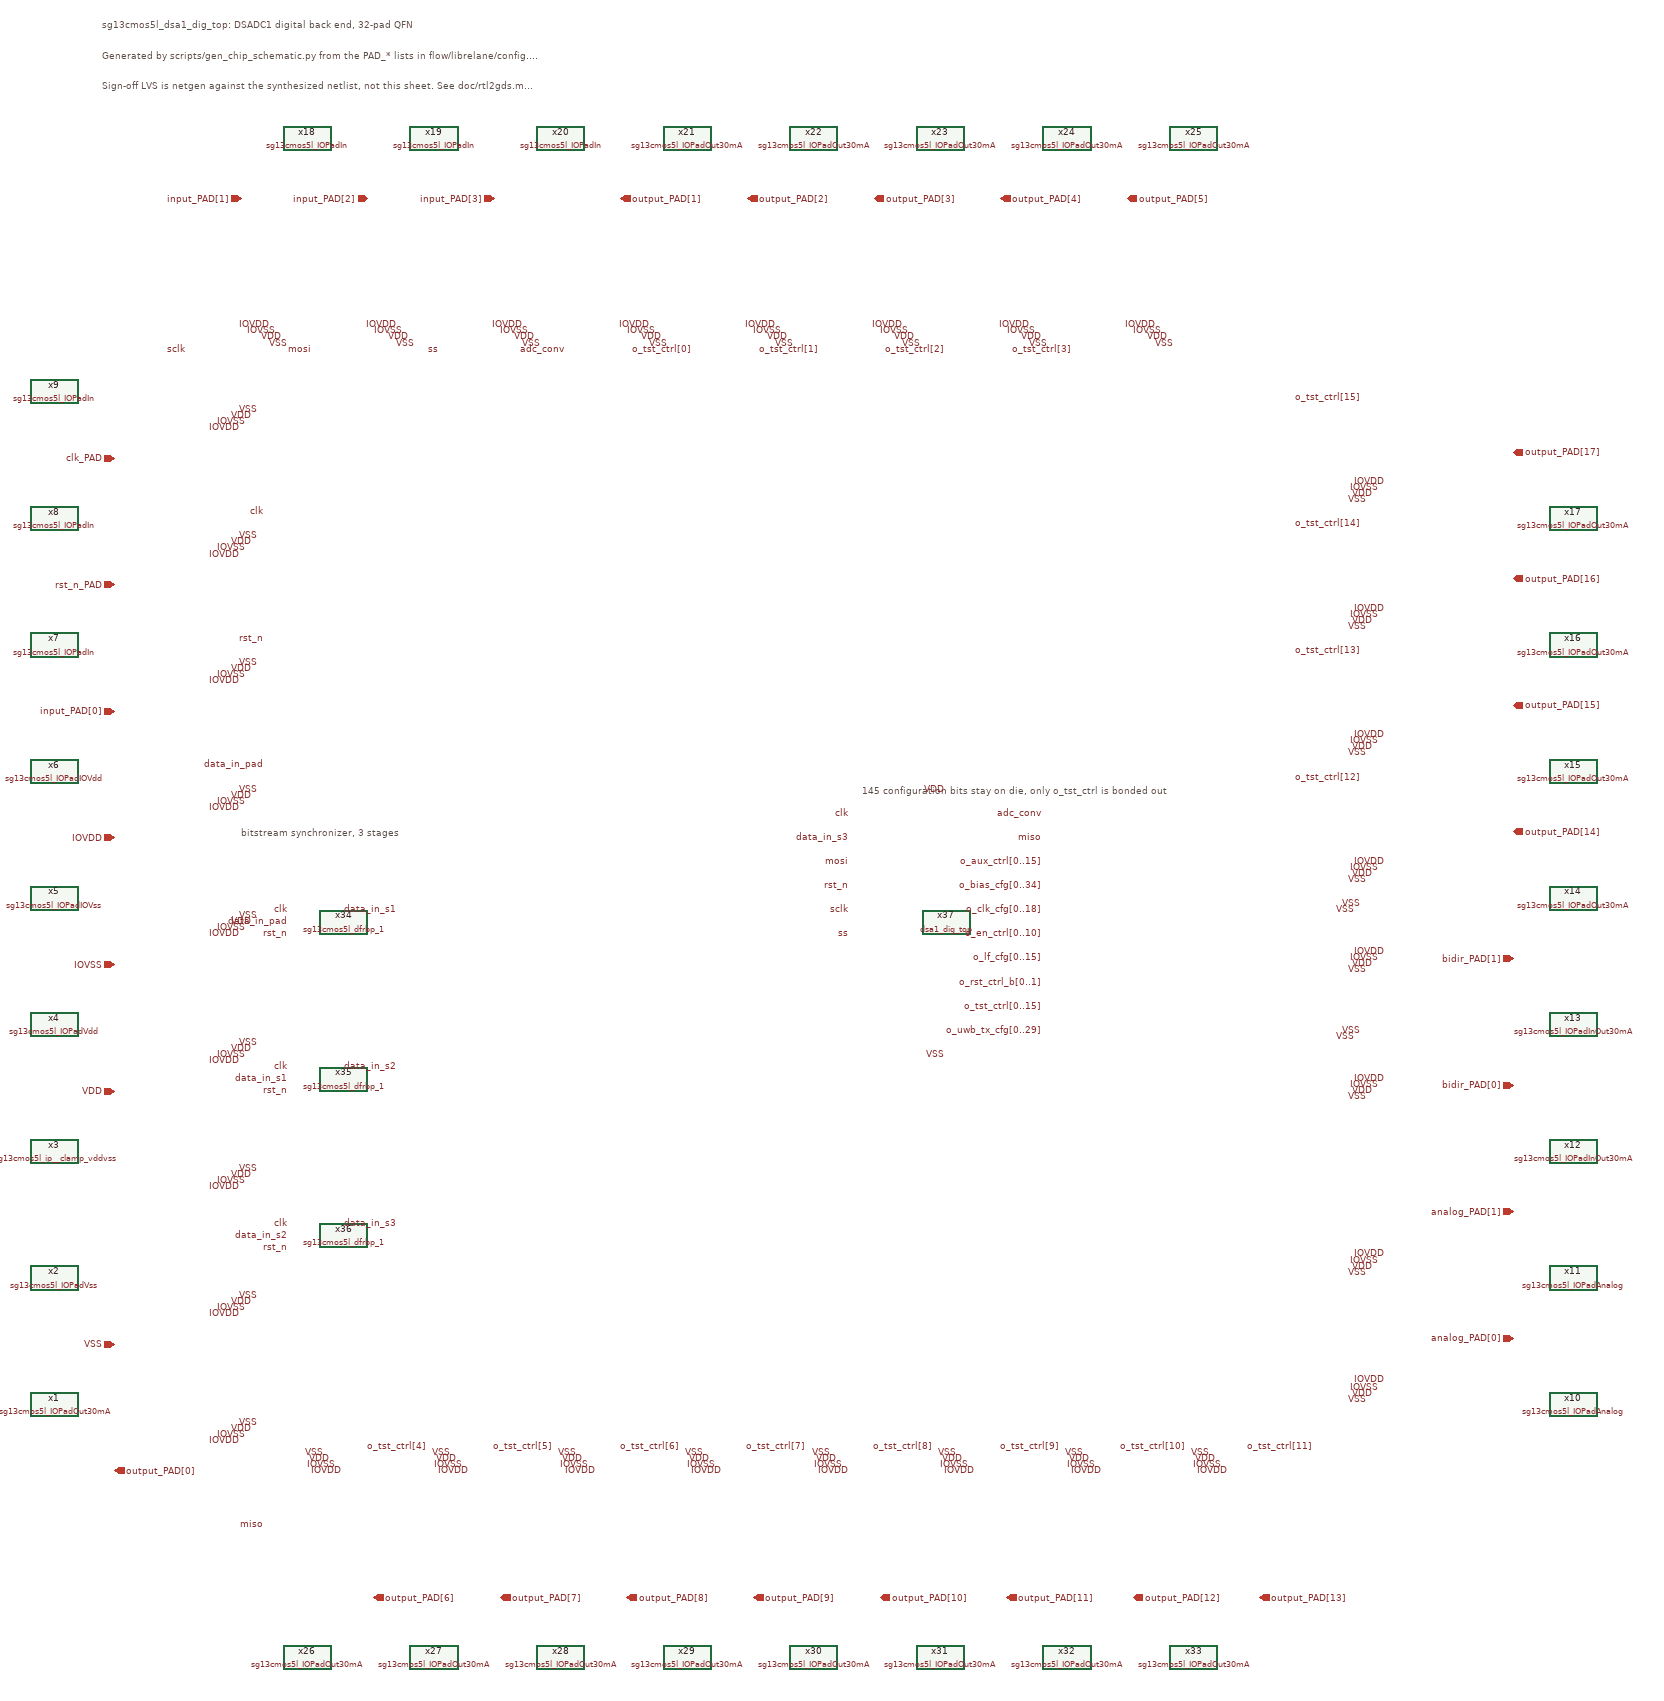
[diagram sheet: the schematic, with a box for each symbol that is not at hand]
v {xschem version=3.4.8RC file_version=1.3}
G {}
K {}
V {}
S {}
F {}
E {}
T {sg13cmos5l_dsa1_dig_top: DSADC1 digital back end, 32-pad QFN} 300 -3200 0 0 0.4 0.4 {}
T {Generated by scripts/gen_chip_schematic.py from the PAD_* lists in flow/librelane/config.yaml. Do not hand edit.} 300 -3150 0 0 0.4 0.4 {}
T {Sign-off LVS is netgen against the synthesized netlist, not this sheet. See doc/rtl2gds.md.} 300 -3100 0 0 0.4 0.4 {}
C {sg13cmos5l_io/sg13cmos5l_IOPadOut30mA.sym} 220 -900 1 0 {name=x1}
C {lab_pin.sym} 560 -870 0 0 {name=l1 sig_type=std_logic lab=VSS}
C {lab_pin.sym} 550 -860 0 0 {name=l2 sig_type=std_logic lab=VDD}
C {lab_pin.sym} 540 -850 0 0 {name=l3 sig_type=std_logic lab=IOVSS}
C {lab_pin.sym} 530 -840 0 0 {name=l4 sig_type=std_logic lab=IOVDD}
C {devices/opin.sym} 320 -790 1 0 {name=p1 lab=output_PAD[0]}
C {lab_pin.sym} 570 -700 0 0 {name=l5 sig_type=std_logic lab=miso}
C {sg13cmos5l_io/sg13cmos5l_IOPadVss.sym} 220 -1110 1 0 {name=x2}
C {lab_pin.sym} 560 -1080 0 0 {name=l6 sig_type=std_logic lab=VSS}
C {lab_pin.sym} 550 -1070 0 0 {name=l7 sig_type=std_logic lab=VDD}
C {lab_pin.sym} 540 -1060 0 0 {name=l8 sig_type=std_logic lab=IOVSS}
C {lab_pin.sym} 530 -1050 0 0 {name=l9 sig_type=std_logic lab=IOVDD}
C {devices/iopin.sym} 320 -1000 1 0 {name=p2 lab=VSS}
C {sg13cmos5l_ip__clamp_vddvss.sym} 220 -1320 1 0 {name=x3}
C {lab_pin.sym} 560 -1290 0 0 {name=l10 sig_type=std_logic lab=VSS}
C {lab_pin.sym} 550 -1280 0 0 {name=l11 sig_type=std_logic lab=VDD}
C {lab_pin.sym} 540 -1270 0 0 {name=l12 sig_type=std_logic lab=IOVSS}
C {lab_pin.sym} 530 -1260 0 0 {name=l13 sig_type=std_logic lab=IOVDD}
C {sg13cmos5l_io/sg13cmos5l_IOPadVdd.sym} 220 -1530 1 0 {name=x4}
C {lab_pin.sym} 560 -1500 0 0 {name=l14 sig_type=std_logic lab=VSS}
C {lab_pin.sym} 550 -1490 0 0 {name=l15 sig_type=std_logic lab=VDD}
C {lab_pin.sym} 540 -1480 0 0 {name=l16 sig_type=std_logic lab=IOVSS}
C {lab_pin.sym} 530 -1470 0 0 {name=l17 sig_type=std_logic lab=IOVDD}
C {devices/iopin.sym} 320 -1420 1 0 {name=p3 lab=VDD}
C {sg13cmos5l_io/sg13cmos5l_IOPadIOVss.sym} 220 -1740 1 0 {name=x5}
C {lab_pin.sym} 560 -1710 0 0 {name=l18 sig_type=std_logic lab=VSS}
C {lab_pin.sym} 550 -1700 0 0 {name=l19 sig_type=std_logic lab=VDD}
C {lab_pin.sym} 540 -1690 0 0 {name=l20 sig_type=std_logic lab=IOVSS}
C {lab_pin.sym} 530 -1680 0 0 {name=l21 sig_type=std_logic lab=IOVDD}
C {devices/iopin.sym} 320 -1630 1 0 {name=p4 lab=IOVSS}
C {sg13cmos5l_io/sg13cmos5l_IOPadIOVdd.sym} 220 -1950 1 0 {name=x6}
C {lab_pin.sym} 560 -1920 0 0 {name=l22 sig_type=std_logic lab=VSS}
C {lab_pin.sym} 550 -1910 0 0 {name=l23 sig_type=std_logic lab=VDD}
C {lab_pin.sym} 540 -1900 0 0 {name=l24 sig_type=std_logic lab=IOVSS}
C {lab_pin.sym} 530 -1890 0 0 {name=l25 sig_type=std_logic lab=IOVDD}
C {devices/iopin.sym} 320 -1840 1 0 {name=p5 lab=IOVDD}
C {sg13cmos5l_io/sg13cmos5l_IOPadIn.sym} 220 -2160 1 0 {name=x7}
C {lab_pin.sym} 560 -2130 0 0 {name=l26 sig_type=std_logic lab=VSS}
C {lab_pin.sym} 550 -2120 0 0 {name=l27 sig_type=std_logic lab=VDD}
C {lab_pin.sym} 540 -2110 0 0 {name=l28 sig_type=std_logic lab=IOVSS}
C {lab_pin.sym} 530 -2100 0 0 {name=l29 sig_type=std_logic lab=IOVDD}
C {devices/ipin.sym} 320 -2050 1 0 {name=p6 lab=input_PAD[0]}
C {lab_pin.sym} 570 -1960 0 0 {name=l30 sig_type=std_logic lab=data_in_pad}
C {sg13cmos5l_io/sg13cmos5l_IOPadIn.sym} 220 -2370 1 0 {name=x8}
C {lab_pin.sym} 560 -2340 0 0 {name=l31 sig_type=std_logic lab=VSS}
C {lab_pin.sym} 550 -2330 0 0 {name=l32 sig_type=std_logic lab=VDD}
C {lab_pin.sym} 540 -2320 0 0 {name=l33 sig_type=std_logic lab=IOVSS}
C {lab_pin.sym} 530 -2310 0 0 {name=l34 sig_type=std_logic lab=IOVDD}
C {devices/ipin.sym} 320 -2260 1 0 {name=p7 lab=rst_n_PAD}
C {lab_pin.sym} 570 -2170 0 0 {name=l35 sig_type=std_logic lab=rst_n}
C {sg13cmos5l_io/sg13cmos5l_IOPadIn.sym} 220 -2580 1 0 {name=x9}
C {lab_pin.sym} 560 -2550 0 0 {name=l36 sig_type=std_logic lab=VSS}
C {lab_pin.sym} 550 -2540 0 0 {name=l37 sig_type=std_logic lab=VDD}
C {lab_pin.sym} 540 -2530 0 0 {name=l38 sig_type=std_logic lab=IOVSS}
C {lab_pin.sym} 530 -2520 0 0 {name=l39 sig_type=std_logic lab=IOVDD}
C {devices/ipin.sym} 320 -2470 1 0 {name=p8 lab=clk_PAD}
C {lab_pin.sym} 570 -2380 0 0 {name=l40 sig_type=std_logic lab=clk}
C {sg13cmos5l_io/sg13cmos5l_IOPadAnalog.sym} 2740 -900 3 0 {name=x10}
C {lab_pin.sym} 2400 -908 0 0 {name=l41 sig_type=std_logic lab=VSS}
C {lab_pin.sym} 2410 -918 0 0 {name=l42 sig_type=std_logic lab=VDD}
C {lab_pin.sym} 2420 -928 0 0 {name=l43 sig_type=std_logic lab=IOVSS}
C {lab_pin.sym} 2430 -940 0 0 {name=l44 sig_type=std_logic lab=IOVDD}
C {devices/iopin.sym} 2640 -1010 3 0 {name=p9 lab=analog_PAD[0]}
C {noconn.sym} 2390 -1000 0 0 {name=nc_an0_pad}
C {noconn.sym} 2390 -1100 0 0 {name=nc_an0_padres}
C {sg13cmos5l_io/sg13cmos5l_IOPadAnalog.sym} 2740 -1110 3 0 {name=x11}
C {lab_pin.sym} 2400 -1118 0 0 {name=l45 sig_type=std_logic lab=VSS}
C {lab_pin.sym} 2410 -1128 0 0 {name=l46 sig_type=std_logic lab=VDD}
C {lab_pin.sym} 2420 -1138 0 0 {name=l47 sig_type=std_logic lab=IOVSS}
C {lab_pin.sym} 2430 -1150 0 0 {name=l48 sig_type=std_logic lab=IOVDD}
C {devices/iopin.sym} 2640 -1220 3 0 {name=p10 lab=analog_PAD[1]}
C {noconn.sym} 2390 -1210 0 0 {name=nc_an1_pad}
C {noconn.sym} 2390 -1310 0 0 {name=nc_an1_padres}
C {sg13cmos5l_io/sg13cmos5l_IOPadInOut30mA.sym} 2740 -1320 3 0 {name=x12}
C {lab_pin.sym} 2400 -1410 0 0 {name=l49 sig_type=std_logic lab=VSS}
C {lab_pin.sym} 2410 -1420 0 0 {name=l50 sig_type=std_logic lab=VDD}
C {lab_pin.sym} 2420 -1430 0 0 {name=l51 sig_type=std_logic lab=IOVSS}
C {lab_pin.sym} 2430 -1440 0 0 {name=l52 sig_type=std_logic lab=IOVDD}
C {devices/iopin.sym} 2640 -1430 3 0 {name=p11 lab=bidir_PAD[0]}
C {lab_pin.sym} 2390 -1520 0 0 {name=l53 sig_type=std_logic lab=VSS}
C {lab_pin.sym} 2380 -1510 0 0 {name=l54 sig_type=std_logic lab=VSS}
C {noconn.sym} 2380 -1330 0 0 {name=nc_bd0_p2c}
C {sg13cmos5l_io/sg13cmos5l_IOPadInOut30mA.sym} 2740 -1530 3 0 {name=x13}
C {lab_pin.sym} 2400 -1620 0 0 {name=l55 sig_type=std_logic lab=VSS}
C {lab_pin.sym} 2410 -1630 0 0 {name=l56 sig_type=std_logic lab=VDD}
C {lab_pin.sym} 2420 -1640 0 0 {name=l57 sig_type=std_logic lab=IOVSS}
C {lab_pin.sym} 2430 -1650 0 0 {name=l58 sig_type=std_logic lab=IOVDD}
C {devices/iopin.sym} 2640 -1640 3 0 {name=p12 lab=bidir_PAD[1]}
C {lab_pin.sym} 2390 -1730 0 0 {name=l59 sig_type=std_logic lab=VSS}
C {lab_pin.sym} 2380 -1720 0 0 {name=l60 sig_type=std_logic lab=VSS}
C {noconn.sym} 2380 -1540 0 0 {name=nc_bd1_p2c}
C {sg13cmos5l_io/sg13cmos5l_IOPadOut30mA.sym} 2740 -1740 3 0 {name=x14}
C {lab_pin.sym} 2400 -1770 0 0 {name=l61 sig_type=std_logic lab=VSS}
C {lab_pin.sym} 2410 -1780 0 0 {name=l62 sig_type=std_logic lab=VDD}
C {lab_pin.sym} 2420 -1790 0 0 {name=l63 sig_type=std_logic lab=IOVSS}
C {lab_pin.sym} 2430 -1800 0 0 {name=l64 sig_type=std_logic lab=IOVDD}
C {devices/opin.sym} 2640 -1850 3 0 {name=p13 lab=output_PAD[14]}
C {lab_pin.sym} 2390 -1940 0 0 {name=l65 sig_type=std_logic lab=o_tst_ctrl[12]}
C {sg13cmos5l_io/sg13cmos5l_IOPadOut30mA.sym} 2740 -1950 3 0 {name=x15}
C {lab_pin.sym} 2400 -1980 0 0 {name=l66 sig_type=std_logic lab=VSS}
C {lab_pin.sym} 2410 -1990 0 0 {name=l67 sig_type=std_logic lab=VDD}
C {lab_pin.sym} 2420 -2000 0 0 {name=l68 sig_type=std_logic lab=IOVSS}
C {lab_pin.sym} 2430 -2010 0 0 {name=l69 sig_type=std_logic lab=IOVDD}
C {devices/opin.sym} 2640 -2060 3 0 {name=p14 lab=output_PAD[15]}
C {lab_pin.sym} 2390 -2150 0 0 {name=l70 sig_type=std_logic lab=o_tst_ctrl[13]}
C {sg13cmos5l_io/sg13cmos5l_IOPadOut30mA.sym} 2740 -2160 3 0 {name=x16}
C {lab_pin.sym} 2400 -2190 0 0 {name=l71 sig_type=std_logic lab=VSS}
C {lab_pin.sym} 2410 -2200 0 0 {name=l72 sig_type=std_logic lab=VDD}
C {lab_pin.sym} 2420 -2210 0 0 {name=l73 sig_type=std_logic lab=IOVSS}
C {lab_pin.sym} 2430 -2220 0 0 {name=l74 sig_type=std_logic lab=IOVDD}
C {devices/opin.sym} 2640 -2270 3 0 {name=p15 lab=output_PAD[16]}
C {lab_pin.sym} 2390 -2360 0 0 {name=l75 sig_type=std_logic lab=o_tst_ctrl[14]}
C {sg13cmos5l_io/sg13cmos5l_IOPadOut30mA.sym} 2740 -2370 3 0 {name=x17}
C {lab_pin.sym} 2400 -2400 0 0 {name=l76 sig_type=std_logic lab=VSS}
C {lab_pin.sym} 2410 -2410 0 0 {name=l77 sig_type=std_logic lab=VDD}
C {lab_pin.sym} 2420 -2420 0 0 {name=l78 sig_type=std_logic lab=IOVSS}
C {lab_pin.sym} 2430 -2430 0 0 {name=l79 sig_type=std_logic lab=IOVDD}
C {devices/opin.sym} 2640 -2480 3 0 {name=p16 lab=output_PAD[17]}
C {lab_pin.sym} 2390 -2570 0 0 {name=l80 sig_type=std_logic lab=o_tst_ctrl[15]}
C {sg13cmos5l_io/sg13cmos5l_IOPadIn.sym} 640 -3000 2 0 {name=x18}
C {lab_pin.sym} 610 -2660 0 0 {name=l81 sig_type=std_logic lab=VSS}
C {lab_pin.sym} 600 -2670 0 0 {name=l82 sig_type=std_logic lab=VDD}
C {lab_pin.sym} 590 -2680 0 0 {name=l83 sig_type=std_logic lab=IOVSS}
C {lab_pin.sym} 580 -2690 0 0 {name=l84 sig_type=std_logic lab=IOVDD}
C {devices/ipin.sym} 530 -2900 2 0 {name=p17 lab=input_PAD[1]}
C {lab_pin.sym} 440 -2650 0 0 {name=l85 sig_type=std_logic lab=sclk}
C {sg13cmos5l_io/sg13cmos5l_IOPadIn.sym} 850 -3000 2 0 {name=x19}
C {lab_pin.sym} 820 -2660 0 0 {name=l86 sig_type=std_logic lab=VSS}
C {lab_pin.sym} 810 -2670 0 0 {name=l87 sig_type=std_logic lab=VDD}
C {lab_pin.sym} 800 -2680 0 0 {name=l88 sig_type=std_logic lab=IOVSS}
C {lab_pin.sym} 790 -2690 0 0 {name=l89 sig_type=std_logic lab=IOVDD}
C {devices/ipin.sym} 740 -2900 2 0 {name=p18 lab=input_PAD[2]}
C {lab_pin.sym} 650 -2650 0 0 {name=l90 sig_type=std_logic lab=mosi}
C {sg13cmos5l_io/sg13cmos5l_IOPadIn.sym} 1060 -3000 2 0 {name=x20}
C {lab_pin.sym} 1030 -2660 0 0 {name=l91 sig_type=std_logic lab=VSS}
C {lab_pin.sym} 1020 -2670 0 0 {name=l92 sig_type=std_logic lab=VDD}
C {lab_pin.sym} 1010 -2680 0 0 {name=l93 sig_type=std_logic lab=IOVSS}
C {lab_pin.sym} 1000 -2690 0 0 {name=l94 sig_type=std_logic lab=IOVDD}
C {devices/ipin.sym} 950 -2900 2 0 {name=p19 lab=input_PAD[3]}
C {lab_pin.sym} 860 -2650 0 0 {name=l95 sig_type=std_logic lab=ss}
C {sg13cmos5l_io/sg13cmos5l_IOPadOut30mA.sym} 1270 -3000 2 0 {name=x21}
C {lab_pin.sym} 1240 -2660 0 0 {name=l96 sig_type=std_logic lab=VSS}
C {lab_pin.sym} 1230 -2670 0 0 {name=l97 sig_type=std_logic lab=VDD}
C {lab_pin.sym} 1220 -2680 0 0 {name=l98 sig_type=std_logic lab=IOVSS}
C {lab_pin.sym} 1210 -2690 0 0 {name=l99 sig_type=std_logic lab=IOVDD}
C {devices/opin.sym} 1160 -2900 2 0 {name=p20 lab=output_PAD[1]}
C {lab_pin.sym} 1070 -2650 0 0 {name=l100 sig_type=std_logic lab=adc_conv}
C {sg13cmos5l_io/sg13cmos5l_IOPadOut30mA.sym} 1480 -3000 2 0 {name=x22}
C {lab_pin.sym} 1450 -2660 0 0 {name=l101 sig_type=std_logic lab=VSS}
C {lab_pin.sym} 1440 -2670 0 0 {name=l102 sig_type=std_logic lab=VDD}
C {lab_pin.sym} 1430 -2680 0 0 {name=l103 sig_type=std_logic lab=IOVSS}
C {lab_pin.sym} 1420 -2690 0 0 {name=l104 sig_type=std_logic lab=IOVDD}
C {devices/opin.sym} 1370 -2900 2 0 {name=p21 lab=output_PAD[2]}
C {lab_pin.sym} 1280 -2650 0 0 {name=l105 sig_type=std_logic lab=o_tst_ctrl[0]}
C {sg13cmos5l_io/sg13cmos5l_IOPadOut30mA.sym} 1690 -3000 2 0 {name=x23}
C {lab_pin.sym} 1660 -2660 0 0 {name=l106 sig_type=std_logic lab=VSS}
C {lab_pin.sym} 1650 -2670 0 0 {name=l107 sig_type=std_logic lab=VDD}
C {lab_pin.sym} 1640 -2680 0 0 {name=l108 sig_type=std_logic lab=IOVSS}
C {lab_pin.sym} 1630 -2690 0 0 {name=l109 sig_type=std_logic lab=IOVDD}
C {devices/opin.sym} 1580 -2900 2 0 {name=p22 lab=output_PAD[3]}
C {lab_pin.sym} 1490 -2650 0 0 {name=l110 sig_type=std_logic lab=o_tst_ctrl[1]}
C {sg13cmos5l_io/sg13cmos5l_IOPadOut30mA.sym} 1900 -3000 2 0 {name=x24}
C {lab_pin.sym} 1870 -2660 0 0 {name=l111 sig_type=std_logic lab=VSS}
C {lab_pin.sym} 1860 -2670 0 0 {name=l112 sig_type=std_logic lab=VDD}
C {lab_pin.sym} 1850 -2680 0 0 {name=l113 sig_type=std_logic lab=IOVSS}
C {lab_pin.sym} 1840 -2690 0 0 {name=l114 sig_type=std_logic lab=IOVDD}
C {devices/opin.sym} 1790 -2900 2 0 {name=p23 lab=output_PAD[4]}
C {lab_pin.sym} 1700 -2650 0 0 {name=l115 sig_type=std_logic lab=o_tst_ctrl[2]}
C {sg13cmos5l_io/sg13cmos5l_IOPadOut30mA.sym} 2110 -3000 2 0 {name=x25}
C {lab_pin.sym} 2080 -2660 0 0 {name=l116 sig_type=std_logic lab=VSS}
C {lab_pin.sym} 2070 -2670 0 0 {name=l117 sig_type=std_logic lab=VDD}
C {lab_pin.sym} 2060 -2680 0 0 {name=l118 sig_type=std_logic lab=IOVSS}
C {lab_pin.sym} 2050 -2690 0 0 {name=l119 sig_type=std_logic lab=IOVDD}
C {devices/opin.sym} 2000 -2900 2 0 {name=p24 lab=output_PAD[5]}
C {lab_pin.sym} 1910 -2650 0 0 {name=l120 sig_type=std_logic lab=o_tst_ctrl[3]}
C {sg13cmos5l_io/sg13cmos5l_IOPadOut30mA.sym} 640 -480 0 0 {name=x26}
C {lab_pin.sym} 670 -820 0 0 {name=l121 sig_type=std_logic lab=VSS}
C {lab_pin.sym} 680 -810 0 0 {name=l122 sig_type=std_logic lab=VDD}
C {lab_pin.sym} 690 -800 0 0 {name=l123 sig_type=std_logic lab=IOVSS}
C {lab_pin.sym} 700 -790 0 0 {name=l124 sig_type=std_logic lab=IOVDD}
C {devices/opin.sym} 750 -580 0 0 {name=p25 lab=output_PAD[6]}
C {lab_pin.sym} 840 -830 0 0 {name=l125 sig_type=std_logic lab=o_tst_ctrl[4]}
C {sg13cmos5l_io/sg13cmos5l_IOPadOut30mA.sym} 850 -480 0 0 {name=x27}
C {lab_pin.sym} 880 -820 0 0 {name=l126 sig_type=std_logic lab=VSS}
C {lab_pin.sym} 890 -810 0 0 {name=l127 sig_type=std_logic lab=VDD}
C {lab_pin.sym} 900 -800 0 0 {name=l128 sig_type=std_logic lab=IOVSS}
C {lab_pin.sym} 910 -790 0 0 {name=l129 sig_type=std_logic lab=IOVDD}
C {devices/opin.sym} 960 -580 0 0 {name=p26 lab=output_PAD[7]}
C {lab_pin.sym} 1050 -830 0 0 {name=l130 sig_type=std_logic lab=o_tst_ctrl[5]}
C {sg13cmos5l_io/sg13cmos5l_IOPadOut30mA.sym} 1060 -480 0 0 {name=x28}
C {lab_pin.sym} 1090 -820 0 0 {name=l131 sig_type=std_logic lab=VSS}
C {lab_pin.sym} 1100 -810 0 0 {name=l132 sig_type=std_logic lab=VDD}
C {lab_pin.sym} 1110 -800 0 0 {name=l133 sig_type=std_logic lab=IOVSS}
C {lab_pin.sym} 1120 -790 0 0 {name=l134 sig_type=std_logic lab=IOVDD}
C {devices/opin.sym} 1170 -580 0 0 {name=p27 lab=output_PAD[8]}
C {lab_pin.sym} 1260 -830 0 0 {name=l135 sig_type=std_logic lab=o_tst_ctrl[6]}
C {sg13cmos5l_io/sg13cmos5l_IOPadOut30mA.sym} 1270 -480 0 0 {name=x29}
C {lab_pin.sym} 1300 -820 0 0 {name=l136 sig_type=std_logic lab=VSS}
C {lab_pin.sym} 1310 -810 0 0 {name=l137 sig_type=std_logic lab=VDD}
C {lab_pin.sym} 1320 -800 0 0 {name=l138 sig_type=std_logic lab=IOVSS}
C {lab_pin.sym} 1330 -790 0 0 {name=l139 sig_type=std_logic lab=IOVDD}
C {devices/opin.sym} 1380 -580 0 0 {name=p28 lab=output_PAD[9]}
C {lab_pin.sym} 1470 -830 0 0 {name=l140 sig_type=std_logic lab=o_tst_ctrl[7]}
C {sg13cmos5l_io/sg13cmos5l_IOPadOut30mA.sym} 1480 -480 0 0 {name=x30}
C {lab_pin.sym} 1510 -820 0 0 {name=l141 sig_type=std_logic lab=VSS}
C {lab_pin.sym} 1520 -810 0 0 {name=l142 sig_type=std_logic lab=VDD}
C {lab_pin.sym} 1530 -800 0 0 {name=l143 sig_type=std_logic lab=IOVSS}
C {lab_pin.sym} 1540 -790 0 0 {name=l144 sig_type=std_logic lab=IOVDD}
C {devices/opin.sym} 1590 -580 0 0 {name=p29 lab=output_PAD[10]}
C {lab_pin.sym} 1680 -830 0 0 {name=l145 sig_type=std_logic lab=o_tst_ctrl[8]}
C {sg13cmos5l_io/sg13cmos5l_IOPadOut30mA.sym} 1690 -480 0 0 {name=x31}
C {lab_pin.sym} 1720 -820 0 0 {name=l146 sig_type=std_logic lab=VSS}
C {lab_pin.sym} 1730 -810 0 0 {name=l147 sig_type=std_logic lab=VDD}
C {lab_pin.sym} 1740 -800 0 0 {name=l148 sig_type=std_logic lab=IOVSS}
C {lab_pin.sym} 1750 -790 0 0 {name=l149 sig_type=std_logic lab=IOVDD}
C {devices/opin.sym} 1800 -580 0 0 {name=p30 lab=output_PAD[11]}
C {lab_pin.sym} 1890 -830 0 0 {name=l150 sig_type=std_logic lab=o_tst_ctrl[9]}
C {sg13cmos5l_io/sg13cmos5l_IOPadOut30mA.sym} 1900 -480 0 0 {name=x32}
C {lab_pin.sym} 1930 -820 0 0 {name=l151 sig_type=std_logic lab=VSS}
C {lab_pin.sym} 1940 -810 0 0 {name=l152 sig_type=std_logic lab=VDD}
C {lab_pin.sym} 1950 -800 0 0 {name=l153 sig_type=std_logic lab=IOVSS}
C {lab_pin.sym} 1960 -790 0 0 {name=l154 sig_type=std_logic lab=IOVDD}
C {devices/opin.sym} 2010 -580 0 0 {name=p31 lab=output_PAD[12]}
C {lab_pin.sym} 2100 -830 0 0 {name=l155 sig_type=std_logic lab=o_tst_ctrl[10]}
C {sg13cmos5l_io/sg13cmos5l_IOPadOut30mA.sym} 2110 -480 0 0 {name=x33}
C {lab_pin.sym} 2140 -820 0 0 {name=l156 sig_type=std_logic lab=VSS}
C {lab_pin.sym} 2150 -810 0 0 {name=l157 sig_type=std_logic lab=VDD}
C {lab_pin.sym} 2160 -800 0 0 {name=l158 sig_type=std_logic lab=IOVSS}
C {lab_pin.sym} 2170 -790 0 0 {name=l159 sig_type=std_logic lab=IOVDD}
C {devices/opin.sym} 2220 -580 0 0 {name=p32 lab=output_PAD[13]}
C {lab_pin.sym} 2310 -830 0 0 {name=l160 sig_type=std_logic lab=o_tst_ctrl[11]}
C {sg13cmos5l_stdcells/sg13cmos5l_dfrbp_1.sym} 700 -1700 0 0 {name=x34}
C {lab_pin.sym} 610 -1720 0 0 {name=l161 sig_type=std_logic lab=clk}
C {lab_pin.sym} 610 -1700 0 0 {name=l162 sig_type=std_logic lab=data_in_pad}
C {lab_pin.sym} 610 -1680 0 0 {name=l163 sig_type=std_logic lab=rst_n}
C {lab_pin.sym} 790 -1720 0 0 {name=l164 sig_type=std_logic lab=data_in_s1}
C {noconn.sym} 790 -1700 0 0 {name=nc_ffqn0}
C {sg13cmos5l_stdcells/sg13cmos5l_dfrbp_1.sym} 700 -1440 0 0 {name=x35}
C {lab_pin.sym} 610 -1460 0 0 {name=l165 sig_type=std_logic lab=clk}
C {lab_pin.sym} 610 -1440 0 0 {name=l166 sig_type=std_logic lab=data_in_s1}
C {lab_pin.sym} 610 -1420 0 0 {name=l167 sig_type=std_logic lab=rst_n}
C {lab_pin.sym} 790 -1460 0 0 {name=l168 sig_type=std_logic lab=data_in_s2}
C {noconn.sym} 790 -1440 0 0 {name=nc_ffqn1}
C {sg13cmos5l_stdcells/sg13cmos5l_dfrbp_1.sym} 700 -1180 0 0 {name=x36}
C {lab_pin.sym} 610 -1200 0 0 {name=l169 sig_type=std_logic lab=clk}
C {lab_pin.sym} 610 -1180 0 0 {name=l170 sig_type=std_logic lab=data_in_s2}
C {lab_pin.sym} 610 -1160 0 0 {name=l171 sig_type=std_logic lab=rst_n}
C {lab_pin.sym} 790 -1200 0 0 {name=l172 sig_type=std_logic lab=data_in_s3}
C {noconn.sym} 790 -1180 0 0 {name=nc_ffqn2}
T {bitstream synchronizer, 3 stages} 530 -1860 0 0 0.4 0.4 {}
C {dsa1_dig_top.sym} 1700 -1700 0 0 {name=x37}
C {lab_pin.sym} 1700 -1920 0 0 {name=l173 sig_type=std_logic lab=VDD}
C {lab_pin.sym} 1700 -1480 0 0 {name=l174 sig_type=std_logic lab=VSS}
C {lab_pin.sym} 1540 -1880 0 0 {name=l175 sig_type=std_logic lab=clk}
C {lab_pin.sym} 1540 -1840 0 0 {name=l176 sig_type=std_logic lab=data_in_s3}
C {lab_pin.sym} 1540 -1800 0 0 {name=l177 sig_type=std_logic lab=mosi}
C {lab_pin.sym} 1540 -1760 0 0 {name=l178 sig_type=std_logic lab=rst_n}
C {lab_pin.sym} 1540 -1720 0 0 {name=l179 sig_type=std_logic lab=sclk}
C {lab_pin.sym} 1540 -1680 0 0 {name=l180 sig_type=std_logic lab=ss}
C {lab_pin.sym} 1860 -1880 0 0 {name=l181 sig_type=std_logic lab=adc_conv}
C {lab_pin.sym} 1860 -1840 0 0 {name=l182 sig_type=std_logic lab=miso}
C {lab_pin.sym} 1860 -1800 0 0 {name=l183 sig_type=std_logic lab=o_aux_ctrl[0..15]}
C {lab_pin.sym} 1860 -1760 0 0 {name=l184 sig_type=std_logic lab=o_bias_cfg[0..34]}
C {lab_pin.sym} 1860 -1720 0 0 {name=l185 sig_type=std_logic lab=o_clk_cfg[0..18]}
C {lab_pin.sym} 1860 -1680 0 0 {name=l186 sig_type=std_logic lab=o_en_ctrl[0..10]}
C {lab_pin.sym} 1860 -1640 0 0 {name=l187 sig_type=std_logic lab=o_lf_cfg[0..15]}
C {lab_pin.sym} 1860 -1600 0 0 {name=l188 sig_type=std_logic lab=o_rst_ctrl_b[0..1]}
C {lab_pin.sym} 1860 -1560 0 0 {name=l189 sig_type=std_logic lab=o_tst_ctrl[0..15]}
C {lab_pin.sym} 1860 -1520 0 0 {name=l190 sig_type=std_logic lab=o_uwb_tx_cfg[0..29]}
T {145 configuration bits stay on die, only o_tst_ctrl is bonded out} 1560 -1930 0 0 0.4 0.4 {}
